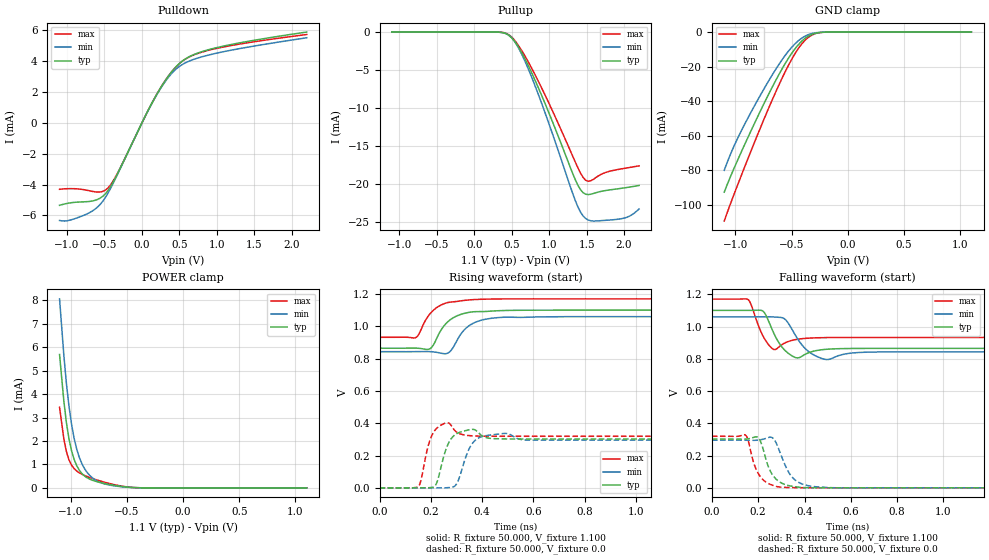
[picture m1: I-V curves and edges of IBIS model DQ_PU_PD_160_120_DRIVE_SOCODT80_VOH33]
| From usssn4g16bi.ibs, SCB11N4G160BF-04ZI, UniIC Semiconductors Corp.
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|   Model DQ_PU_PD_160_120_DRIVE_SOCODT80_VOH33
[Model] DQ_PU_PD_160_120_DRIVE_SOCODT80_VOH33
Model_type I/O
Polarity   Inverting
Vinl =  98.000mV
Vinh =  0.268V
Vmeas =  0.183V
Rref =  50.000
Vref =  0.183V
C_comp   1.020pF   1.010pF   1.030pF
[Model Spec]
Vinh   0.268V   0.262V   0.280V
Vinl   98.000mV   92.000mV   0.110V
Vmeas   0.183V   0.177V   0.195V
Vref   0.183V   0.177V   0.195V
Rref   50.000   NA   NA
[Temperature Range]   25.000   85.000   -40.000
[Voltage Range]   1.100V   1.060V   1.170V
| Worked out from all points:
|   slope of the pulldown table from 0 to 0.165 V, typ, clamps not added: 105 ohm
|   GND clamp passes 1 mA (typ) near -0.30 V on its own axis
|   POWER clamp passes 1 mA (typ) near -0.95 V on its own axis
|   rising waveform, R_fixture 50.000, V_fixture 1.100: 20-80 % time 68.7ps typ, 69.3ps min, 67.4ps max; typ from 0.864 V to 1.1 V
|   rising waveform, R_fixture 50.000, V_fixture 0.0: 20-80 % time 30.7ps typ, 37.6ps min, 25.1ps max; typ from 0 V to 0.302 V
|   falling waveform, R_fixture 50.000, V_fixture 1.100: 20-80 % time 45.3ps typ, 56.9ps min, 35.5ps max; typ from 1.1 V to 0.864 V
|   falling waveform, R_fixture 50.000, V_fixture 0.0: 20-80 % time 51.8ps typ, 61.5ps min, 48.7ps max; typ from 0.302 V to 0 V
[Pulldown]
|Voltage   I(typ)   I(min)   I(max)
-1.1V     -5.34mA    -6.324mA   -4.302mA
-964mV    -5.187mA   -6.308mA   -4.26mA
-692mV    -5.084mA   -5.795mA   -4.408mA
-556mV    -4.87mA    -5.274mA   -4.475mA
-454mV    -4.386mA   -4.558mA   -4.222mA
-318mV    -3.209mA   -3.256mA   -3.18mA
158mV     1.503mA    1.489mA    1.509mA
328mV     2.865mA    2.797mA    2.867mA
498mV     3.844mA    3.653mA    3.837mA
668mV     4.377mA    4.078mA    4.359mA
940mV     4.811mA    4.458mA    4.768mA
2.2V      5.891mA    5.519mA    5.73mA
[Pullup]
|Voltage   I(typ)   I(min)   I(max)
-1.1V     1.606nA    7.718nA    0A
296mV     -8.845uA   -10.59uA   -4.922uA
466mV     -464.7uA   -456.5uA   -387.5uA
602mV     -2.18mA    -2.299mA   -1.951mA
738mV     -4.764mA   -5.249mA   -4.236mA
976mV     -10.14mA   -11.47mA   -8.932mA
1.35V     -19.45mA   -22.19mA   -17.13mA
1.452V    -21.12mA   -24.17mA   -19.11mA
1.554V    -21.33mA   -24.82mA   -19.57mA
1.928V    -20.6mA    -24.61mA   -18.06mA
2.064V    -20.4mA    -24.25mA   -17.83mA
2.2V      -20.18mA   -23.28mA   -17.6mA
[GND_clamp]
|Voltage   I(typ)   I(min)   I(max)
-1.1V     -92.78mA   -80.14mA   -109.5mA
-1.031V   -81.73mA   -68.77mA   -97.17mA
-939mV    -68.18mA   -56.07mA   -81.64mA
-801mV    -48.85mA   -39.25mA   -59.15mA
-663mV    -30.71mA   -23.84mA   -37.89mA
-571mV    -19.76mA   -14.75mA   -24.85mA
-479mV    -10.5mA    -7.415mA   -13.5mA
-410mV    -5.313mA   -3.546mA   -6.916mA
-341mV    -2.007mA   -1.262mA   -2.59mA
-272mV    -506.9uA   -323.5uA   -609.8uA
-180mV    -45.65uA   -36.06uA   -43.55uA
1.1V      0A         0A         0A
[POWER_clamp]
|Voltage   I(typ)   I(min)   I(max)
-1.1V     5.691mA    8.066mA    3.44mA
-1.062V   3.709mA    5.665mA    2.092mA
-1.039V   2.781mA    4.457mA    1.546mA
-1.016V   2.086mA    3.48mA     1.193mA
-993mV    1.578mA    2.707mA    966.5uA
-970mV    1.21mA     2.107mA    818.5uA
-924mV    750.8uA    1.296mA    641.3uA
-878mV    507uA      821.4uA    530.2uA
-809mV    327.4uA    430uA      403.3uA
-694mV    178.4uA    161uA      233uA
-464mV    19.89uA    15.19uA    23.61uA
1.1V      0A         0A         0A
[Ramp]
| variable   typ   min   max
dV/dt_r   0.181/30.812p   0.177/37.700p   0.192/25.195p
dV/dt_f   0.141/45.332p   0.130/56.925p   0.143/35.518p
R_load = 50.000
[Rising Waveform]
R_fixture= 50.000
V_fixture= 1.100
V_fixture_min= 1.060
V_fixture_max= 1.170
|time   V(typ)   V(min)   V(max)
0s        864.4mV    842.9mV    932.1mV
141ps     864.9mV    843.2mV    930.3mV
195ps     859.6mV    843.4mV    1.074V
262ps     1.022V     831.6mV    1.146V
281ps     1.046V     855.2mV    1.151V
328ps     1.079V     973.9mV    1.16V
374ps     1.091V     1.025V     1.166V
462ps     1.096V     1.054V     1.169V
630ps     1.1V       1.059V     1.17V
3ns       1.1V       1.06V      1.17V
[Rising Waveform]
R_fixture= 50.000
V_fixture= 0.0
V_fixture_min= 0.0
V_fixture_max= 0.0
|time   V(typ)   V(min)   V(max)
0s        4.356uV    8.339uV    1.031uV
151ps     -96.84uV   43.88uV    7.108mV
190ps     269uV      3.949uV    260.9mV
217ps     12.82mV    -102.3uV   358.3mV
263ps     254.9mV    541.9uV    403.3mV
300ps     334.6mV    23.14mV    345.7mV
370ps     359.9mV    289.8mV    321.2mV
482ps     302.8mV    336.1mV    319.2mV
583ps     302.1mV    295.2mV    319.2mV
3ns       302.1mV    295.1mV    319.2mV
[Falling Waveform]
R_fixture= 50.000
V_fixture= 1.100
V_fixture_min= 1.060
V_fixture_max= 1.170
|time   V(typ)   V(min)   V(max)
0s        1.1V       1.06V      1.17V
156ps     1.1V       1.06V      1.167V
221ps     1.095V     1.06V      940.5mV
272ps     944.7mV    1.059V     856.9mV
318ps     848.8mV    1.042V     899.9mV
363ps     806.5mV    940.3mV    919.2mV
416ps     836.3mV    846.6mV    927.7mV
494ps     858.5mV    795.1mV    931.2mV
697ps     864.3mV    841.7mV    932.1mV
3ns       864.4mV    842.9mV    932.1mV
[Falling Waveform]
R_fixture= 50.000
V_fixture= 0.0
V_fixture_min= 0.0
V_fixture_max= 0.0
|time   V(typ)   V(min)   V(max)
0s        302.1mV    295.1mV    319.2mV
146ps     301.7mV    294.7mV    325.7mV
196ps     314.5mV    295mV      99.96mV
212ps     280.1mV    298.2mV    63.94mV
262ps     80.07mV    309.8mV    15.6mV
300ps     29.99mV    197.7mV    3.681mV
334ps     12.87mV    90.53mV    1.578mV
370ps     4.585mV    37.36mV    634.6uV
515ps     63.07uV    492.2uV    16.12uV
3ns       4.394uV    8.237uV    1.068uV
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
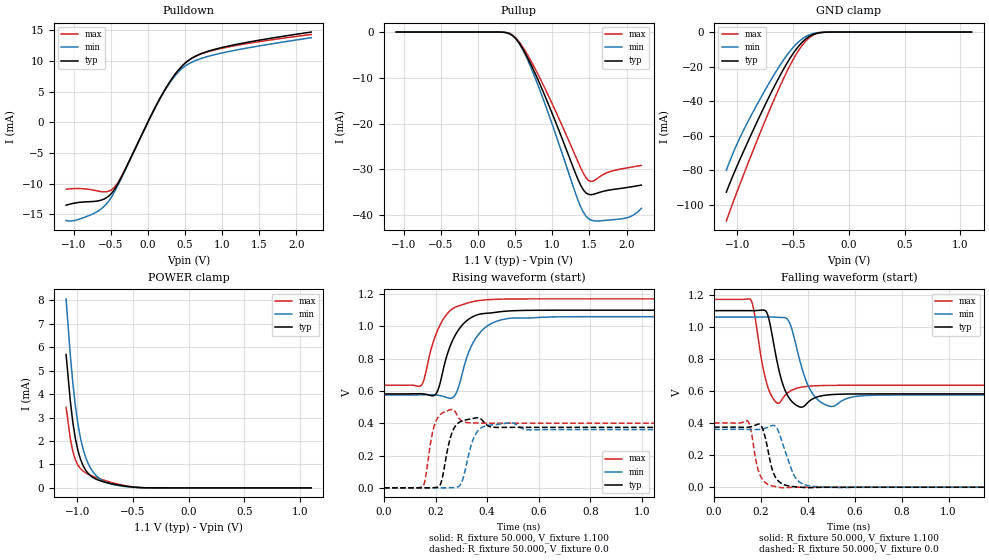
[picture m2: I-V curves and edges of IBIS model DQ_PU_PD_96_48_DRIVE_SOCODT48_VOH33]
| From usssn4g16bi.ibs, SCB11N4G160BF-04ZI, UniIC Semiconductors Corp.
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|   Model DQ_PU_PD_96_48_DRIVE_SOCODT48_VOH33
[Model] DQ_PU_PD_96_48_DRIVE_SOCODT48_VOH33
Model_type I/O
Polarity   Inverting
Vinl =  98.000mV
Vinh =  0.268V
Vmeas =  0.183V
Rref =  50.000
Vref =  0.183V
C_comp   1.020pF   1.010pF   1.030pF
[Model Spec]
Vinh   0.268V   0.262V   0.280V
Vinl   98.000mV   92.000mV   0.110V
Vmeas   0.183V   0.177V   0.195V
Vref   0.183V   0.177V   0.195V
Rref   50.000   NA   NA
[Temperature Range]   25.000   85.000   -40.000
[Voltage Range]   1.100V   1.060V   1.170V
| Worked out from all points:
|   slope of the pulldown table from 0 to 0.165 V, typ, clamps not added: 42.3 ohm
|   GND clamp passes 1 mA (typ) near -0.30 V on its own axis
|   POWER clamp passes 1 mA (typ) near -0.95 V on its own axis
|   rising waveform, R_fixture 50.000, V_fixture 1.100: 20-80 % time 74.2ps typ, 75.6ps min, 72ps max; typ from 0.582 V to 1.1 V
|   rising waveform, R_fixture 50.000, V_fixture 0.0: 20-80 % time 27.6ps typ, 34.1ps min, 22.6ps max; typ from 0 V to 0.374 V
|   falling waveform, R_fixture 50.000, V_fixture 1.100: 20-80 % time 42.9ps typ, 54.3ps min, 34.6ps max; typ from 1.1 V to 0.582 V
|   falling waveform, R_fixture 50.000, V_fixture 0.0: 20-80 % time 37.6ps typ, 53.2ps min, 33.2ps max; typ from 0.374 V to 0 V
[Pulldown]
|Voltage   I(typ)   I(min)   I(max)
-1.1V     -13.51mA   -16mA      -10.91mA
-964mV    -13.12mA   -15.94mA   -10.79mA
-692mV    -12.85mA   -14.63mA   -11.15mA
-556mV    -12.29mA   -13.29mA   -11.31mA
-454mV    -11.04mA   -11.45mA   -10.65mA
-318mV    -8.03mA    -8.142mA   -7.964mA
158mV     3.751mA    3.718mA    3.768mA
328mV     7.153mA    6.985mA    7.158mA
498mV     9.598mA    9.123mA    9.581mA
668mV     10.93mA    10.18mA    10.89mA
940mV     12.01mA    11.13mA    11.91mA
2.2V      14.71mA    13.78mA    14.31mA
[Pullup]
|Voltage   I(typ)   I(min)   I(max)
-1.1V     2.6nA      12.94nA    0A
296mV     -14.74uA   -17.65uA   -8.203uA
466mV     -773.5uA   -759.8uA   -645.2uA
602mV     -3.625mA   -3.82mA    -3.244mA
738mV     -7.914mA   -8.716mA   -7.039mA
976mV     -16.84mA   -19.04mA   -14.84mA
1.35V     -32.28mA   -36.82mA   -28.44mA
1.452V    -35.08mA   -40.12mA   -31.74mA
1.554V    -35.42mA   -41.2mA    -32.53mA
1.928V    -34.12mA   -40.78mA   -29.88mA
2.064V    -33.78mA   -40.2mA    -29.49mA
2.2V      -33.41mA   -38.49mA   -29.11mA
[GND_clamp]
|Voltage   I(typ)   I(min)   I(max)
-1.1V     -92.78mA   -80.14mA   -109.5mA
-1.031V   -81.73mA   -68.77mA   -97.17mA
-939mV    -68.18mA   -56.07mA   -81.64mA
-801mV    -48.85mA   -39.25mA   -59.15mA
-663mV    -30.71mA   -23.84mA   -37.89mA
-571mV    -19.76mA   -14.75mA   -24.85mA
-479mV    -10.5mA    -7.415mA   -13.5mA
-410mV    -5.313mA   -3.546mA   -6.916mA
-341mV    -2.007mA   -1.262mA   -2.59mA
-272mV    -506.9uA   -323.5uA   -609.8uA
-180mV    -45.65uA   -36.06uA   -43.55uA
1.1V      0A         0A         0A
[POWER_clamp]
|Voltage   I(typ)   I(min)   I(max)
-1.1V     5.691mA    8.066mA    3.44mA
-1.062V   3.709mA    5.665mA    2.092mA
-1.039V   2.781mA    4.457mA    1.546mA
-1.016V   2.086mA    3.48mA     1.193mA
-993mV    1.578mA    2.707mA    966.5uA
-970mV    1.21mA     2.107mA    818.5uA
-924mV    750.8uA    1.296mA    641.3uA
-878mV    507uA      821.4uA    530.2uA
-809mV    327.4uA    430uA      403.3uA
-694mV    178.4uA    161uA      233uA
-464mV    19.89uA    15.19uA    23.61uA
1.1V      0A         0A         0A
[Ramp]
| variable   typ   min   max
dV/dt_r   0.225/27.758p   0.216/34.246p   0.240/22.738p
dV/dt_f   0.311/42.858p   0.291/54.332p   0.321/34.656p
R_load = 50.000
[Rising Waveform]
R_fixture= 50.000
V_fixture= 1.100
V_fixture_min= 1.060
V_fixture_max= 1.170
|time   V(typ)   V(min)   V(max)
0s        581.6mV    575.3mV    635mV
144ps     582.5mV    575.8mV    633.4mV
203ps     584.3mV    575.4mV    955.7mV
267ps     915.3mV    559mV      1.11V
289ps     977.7mV    622.3mV    1.126V
330ps     1.046V     845mV      1.147V
376ps     1.077V     967.2mV    1.161V
474ps     1.094V     1.046V     1.169V
659ps     1.1V       1.058V     1.17V
3ns       1.1V       1.06V      1.17V
[Rising Waveform]
R_fixture= 50.000
V_fixture= 0.0
V_fixture_min= 0.0
V_fixture_max= 0.0
|time   V(typ)   V(min)   V(max)
0s        2.898uV    5.55uV     685nV
151ps     -60.59uV   37.16uV    9.646mV
200ps     1.978mV    -8.08uV    406.5mV
222ps     34.47mV    78.67uV    458.6mV
263ps     337.1mV    792.3uV    485.3mV
301ps     413.2mV    32.27mV    415.6mV
343ps     428.8mV    286.6mV    401.8mV
367ps     433.5mV    357.5mV    400.8mV
485ps     374.4mV    401.3mV    400.4mV
3ns       374.4mV    360.6mV    400.4mV
[Falling Waveform]
R_fixture= 50.000
V_fixture= 1.100
V_fixture_min= 1.060
V_fixture_max= 1.170
|time   V(typ)   V(min)   V(max)
0s        1.1V       1.06V      1.17V
158ps     1.1V       1.06V      1.164V
224ps     1.09V      1.06V      649.5mV
272ps     759.8mV    1.058V     522.9mV
319ps     558.3mV    1.033V     593.7mV
354ps     508mV      857.7mV    617mV
414ps     544.5mV    596.5mV    630.4mV
495ps     576.3mV    503.8mV    634.2mV
697ps     581.5mV    573.8mV    635mV
3ns       581.6mV    575.3mV    635mV
[Falling Waveform]
R_fixture= 50.000
V_fixture= 0.0
V_fixture_min= 0.0
V_fixture_max= 0.0
|time   V(typ)   V(min)   V(max)
0s        374.4mV    360.6mV    400.4mV
145ps     373.8mV    360mV      410mV
182ps     390.4mV    359.3mV    141.4mV
197ps     389.9mV    360.7mV    72.57mV
216ps     321.7mV    366.7mV    31.85mV
252ps     93.55mV    385.4mV    7.282mV
291ps     20.9mV     278.6mV    -3.476mV
348ps     3.076mV    57.54mV    -486.2uV
434ps     -1.192mV   3.908mV    -15.36uV
3ns       1.179uV    5.421uV    359.7nV
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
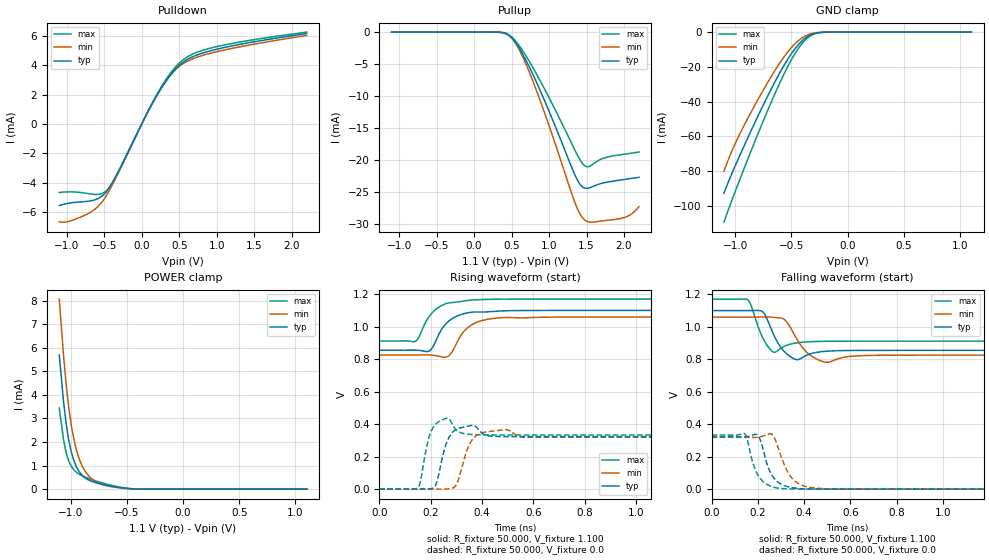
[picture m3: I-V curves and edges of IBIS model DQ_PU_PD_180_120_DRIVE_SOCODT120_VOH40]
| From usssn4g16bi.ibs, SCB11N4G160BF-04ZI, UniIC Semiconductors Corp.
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|   Model DQ_PU_PD_180_120_DRIVE_SOCODT120_VOH40
[Model] DQ_PU_PD_180_120_DRIVE_SOCODT120_VOH40
Model_type I/O
Polarity   Inverting
Vinl =  0.135V
Vinh =  0.305V
Vmeas =  0.220V
Rref =  50.000
Vref =  0.220V
C_comp   1.020pF   1.010pF   1.030pF
[Model Spec]
Vinh   0.305V   0.297V   0.319V
Vinl   0.135V   0.127V   0.149V
Vmeas   0.220V   0.212V   0.234V
Vref   0.220V   0.212V   0.234V
Rref   50.000   NA   NA
[Temperature Range]   25.000   85.000   -40.000
[Voltage Range]   1.100V   1.060V   1.170V
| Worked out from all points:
|   slope of the pulldown table from 0 to 0.165 V, typ, clamps not added: 102 ohm
|   GND clamp passes 1 mA (typ) near -0.30 V on its own axis
|   POWER clamp passes 1 mA (typ) near -0.95 V on its own axis
|   rising waveform, R_fixture 50.000, V_fixture 1.100: 20-80 % time 67.5ps typ, 68.8ps min, 68.1ps max; typ from 0.855 V to 1.1 V
|   rising waveform, R_fixture 50.000, V_fixture 0.0: 20-80 % time 28.6ps typ, 36.4ps min, 22.7ps max; typ from 0 V to 0.323 V
|   falling waveform, R_fixture 50.000, V_fixture 1.100: 20-80 % time 46.6ps typ, 59.8ps min, 37.4ps max; typ from 1.1 V to 0.855 V
|   falling waveform, R_fixture 50.000, V_fixture 0.0: 20-80 % time 51.5ps typ, 61.4ps min, 49.1ps max; typ from 0.323 V to 0 V
[Pulldown]
|Voltage   I(typ)   I(min)   I(max)
-1.1V     -5.559mA   -6.673mA   -4.673mA
-964mV    -5.394mA   -6.634mA   -4.631mA
-692mV    -5.255mA   -6.046mA   -4.769mA
-556mV    -5.011mA   -5.482mA   -4.784mA
-454mV    -4.503mA   -4.733mA   -4.479mA
-318mV    -3.293mA   -3.384mA   -3.363mA
158mV     1.547mA    1.562mA    1.602mA
328mV     2.959mA    2.962mA    3.064mA
498mV     3.986mA    3.92mA     4.137mA
668mV     4.555mA    4.415mA    4.737mA
940mV     5.019mA    4.85mA     5.2mA
2.2V      6.168mA    6.037mA    6.263mA
[Pullup]
|Voltage   I(typ)   I(min)   I(max)
-1.1V     1.8nA      9.024nA    0A
296mV     -10.32uA   -12.39uA   -5.289uA
466mV     -538.9uA   -538.1uA   -421.8uA
602mV     -2.521mA   -2.744mA   -2.134mA
738mV     -5.508mA   -6.307mA   -4.628mA
976mV     -11.74mA   -13.85mA   -9.734mA
1.35V     -22.51mA   -26.87mA   -18.62mA
1.452V    -24.32mA   -29.17mA   -20.7mA
1.52V     -24.46mA   -29.71mA   -21.11mA
1.724V    -23.63mA   -29.56mA   -19.76mA
1.962V    -23.16mA   -29.18mA   -19.2mA
2.2V      -22.76mA   -27.35mA   -18.79mA
[GND_clamp]
|Voltage   I(typ)   I(min)   I(max)
-1.1V     -92.78mA   -80.14mA   -109.5mA
-1.031V   -81.73mA   -68.77mA   -97.17mA
-939mV    -68.18mA   -56.07mA   -81.64mA
-801mV    -48.85mA   -39.25mA   -59.15mA
-663mV    -30.71mA   -23.84mA   -37.89mA
-571mV    -19.76mA   -14.75mA   -24.85mA
-479mV    -10.5mA    -7.415mA   -13.5mA
-410mV    -5.313mA   -3.546mA   -6.916mA
-341mV    -2.007mA   -1.262mA   -2.59mA
-272mV    -506.9uA   -323.5uA   -609.8uA
-180mV    -45.65uA   -36.06uA   -43.55uA
1.1V      0A         0A         0A
[POWER_clamp]
|Voltage   I(typ)   I(min)   I(max)
-1.1V     5.691mA    8.066mA    3.44mA
-1.062V   3.709mA    5.665mA    2.092mA
-1.039V   2.781mA    4.457mA    1.546mA
-1.016V   2.086mA    3.48mA     1.193mA
-993mV    1.578mA    2.707mA    966.5uA
-970mV    1.21mA     2.107mA    818.5uA
-924mV    750.8uA    1.296mA    641.3uA
-878mV    507uA      821.4uA    530.2uA
-809mV    327.4uA    430uA      403.3uA
-694mV    178.4uA    161uA      233uA
-464mV    19.89uA    15.19uA    23.61uA
1.1V      0A         0A         0A
[Ramp]
| variable   typ   min   max
dV/dt_r   0.194/28.684p   0.192/36.443p   0.200/22.890p
dV/dt_f   0.147/46.635p   0.141/59.926p   0.155/37.444p
R_load = 50.000
[Rising Waveform]
R_fixture= 50.000
V_fixture= 1.100
V_fixture_min= 1.060
V_fixture_max= 1.170
|time   V(typ)   V(min)   V(max)
0s        855mV      825.4mV    911.8mV
140ps     855.6mV    825.7mV    909.3mV
195ps     850.3mV    825.9mV    1.064V
262ps     1.021V     813.4mV    1.143V
281ps     1.046V     838.9mV    1.148V
327ps     1.079V     965.4mV    1.158V
378ps     1.091V     1.026V     1.166V
479ps     1.097V     1.056V     1.169V
726ps     1.1V       1.06V      1.17V
3ns       1.1V       1.06V      1.17V
[Rising Waveform]
R_fixture= 50.000
V_fixture= 0.0
V_fixture_min= 0.0
V_fixture_max= 0.0
|time   V(typ)   V(min)   V(max)
0s        4.316uV    8.22uV     1.011uV
150ps     -148.4uV   53.97uV    7.123mV
192ps     690.2uV    -17.05uV   309.1mV
217ps     15.99mV    -187.8uV   395.2mV
262ps     284.7mV    542.2uV    436.2mV
300ps     366.9mV    26.4mV     364.2mV
368ps     391.6mV    315.2mV    335.3mV
491ps     323.5mV    365.8mV    333.3mV
569ps     323.1mV    318.8mV    333.3mV
3ns       323.1mV    319.3mV    333.3mV
[Falling Waveform]
R_fixture= 50.000
V_fixture= 1.100
V_fixture_min= 1.060
V_fixture_max= 1.170
|time   V(typ)   V(min)   V(max)
0s        1.1V       1.06V      1.17V
157ps     1.1V       1.06V      1.166V
223ps     1.09V      1.06V      926.9mV
272ps     940.7mV    1.058V     843.2mV
316ps     845.3mV    1.044V     881.2mV
363ps     799.3mV    937.8mV    900.1mV
417ps     828.5mV    836.1mV    907.8mV
496ps     849.6mV    781.2mV    911mV
698ps     854.9mV    824.3mV    911.8mV
3ns       855mV      825.4mV    911.8mV
[Falling Waveform]
R_fixture= 50.000
V_fixture= 0.0
V_fixture_min= 0.0
V_fixture_max= 0.0
|time   V(typ)   V(min)   V(max)
0s        323.1mV    319.3mV    333.3mV
143ps     322.4mV    318.8mV    341mV
196ps     335.8mV    319.1mV    98.08mV
211ps     300.6mV    322.5mV    64.19mV
261ps     85.14mV    337.2mV    15.54mV
300ps     30.86mV    203.1mV    3.484mV
336ps     12.51mV    88.61mV    1.392mV
370ps     4.678mV    38.36mV    583.7uV
511ps     71.96uV    777.5uV    15.69uV
3ns       4.316uV    8.145uV    1.06uV
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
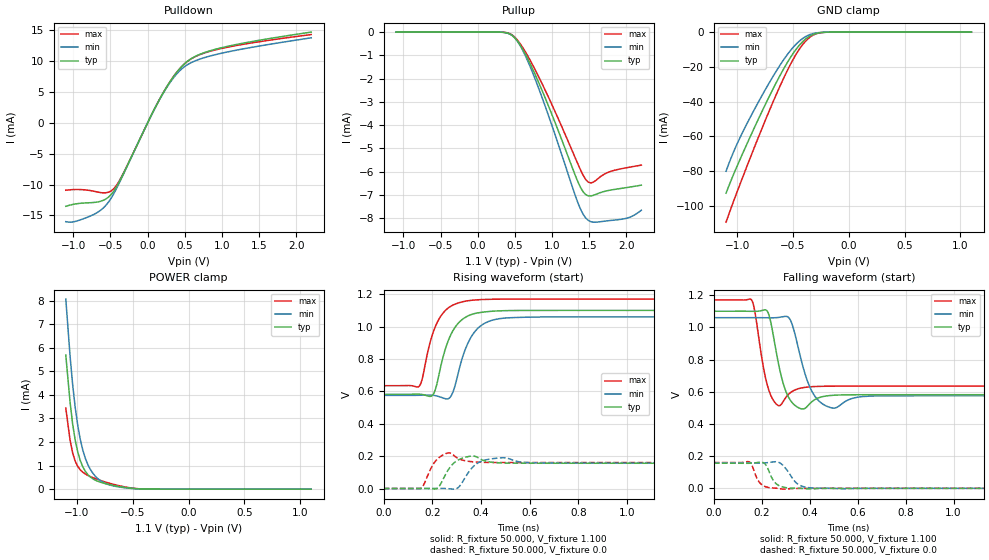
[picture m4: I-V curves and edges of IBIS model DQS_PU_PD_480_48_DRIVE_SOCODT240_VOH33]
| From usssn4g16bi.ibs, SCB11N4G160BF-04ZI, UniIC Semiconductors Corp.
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|   Model DQS_PU_PD_480_48_DRIVE_SOCODT240_VOH33
[Model] DQS_PU_PD_480_48_DRIVE_SOCODT240_VOH33
Model_type I/O
Polarity   Inverting
Vinl =  98.000mV
Vinh =  0.268V
Vmeas =  0.183V
Rref =  50.000
Vref =  0.183V
C_comp   1.020pF   1.010pF   1.030pF
[Model Spec]
Vinh   0.268V   0.262V   0.280V
Vinl   98.000mV   92.000mV   0.110V
Vmeas   0.183V   0.177V   0.195V
Vref   0.183V   0.177V   0.195V
Rref   50.000   NA   NA
[Temperature Range]   25.000   85.000   -40.000
[Voltage Range]   1.100V   1.060V   1.170V
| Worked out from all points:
|   slope of the pulldown table from 0 to 0.165 V, typ, clamps not added: 42.3 ohm
|   GND clamp passes 1 mA (typ) near -0.30 V on its own axis
|   POWER clamp passes 1 mA (typ) near -0.95 V on its own axis
|   rising waveform, R_fixture 50.000, V_fixture 1.100: 20-80 % time 69.1ps typ, 71.9ps min, 66.6ps max; typ from 0.582 V to 1.1 V
|   rising waveform, R_fixture 50.000, V_fixture 0.0: 20-80 % time 34.3ps typ, 42ps min, 28.1ps max; typ from 0 V to 0.156 V
|   falling waveform, R_fixture 50.000, V_fixture 1.100: 20-80 % time 41ps typ, 51.7ps min, 33ps max; typ from 1.1 V to 0.582 V
|   falling waveform, R_fixture 50.000, V_fixture 0.0: 20-80 % time 33.6ps typ, 47.7ps min, 30.2ps max; typ from 0.156 V to 0 V
[Pulldown]
|Voltage   I(typ)   I(min)   I(max)
-1.1V     -13.51mA   -16mA      -10.91mA
-964mV    -13.12mA   -15.94mA   -10.79mA
-692mV    -12.85mA   -14.63mA   -11.15mA
-556mV    -12.29mA   -13.29mA   -11.31mA
-454mV    -11.04mA   -11.45mA   -10.65mA
-318mV    -8.03mA    -8.142mA   -7.964mA
158mV     3.751mA    3.718mA    3.768mA
328mV     7.153mA    6.985mA    7.158mA
498mV     9.598mA    9.123mA    9.581mA
668mV     10.93mA    10.18mA    10.89mA
940mV     12.01mA    11.13mA    11.91mA
2.2V      14.71mA    13.78mA    14.31mA
[Pullup]
|Voltage   I(typ)   I(min)   I(max)
-1.1V     500pA      2.606nA    0A
296mV     -2.948uA   -3.529uA   -1.641uA
466mV     -154.8uA   -152.1uA   -129.1uA
602mV     -725.8uA   -765uA     -649.5uA
738mV     -1.585mA   -1.746mA   -1.41mA
976mV     -3.374mA   -3.816mA   -2.972mA
1.316V    -6.198mA   -7.072mA   -5.446mA
1.452V    -6.989mA   -7.995mA   -6.341mA
1.52V     -7.049mA   -8.152mA   -6.489mA
1.724V    -6.835mA   -8.124mA   -6.072mA
1.928V    -6.723mA   -8.051mA   -5.878mA
2.2V      -6.582mA   -7.66mA    -5.721mA
[GND_clamp]
|Voltage   I(typ)   I(min)   I(max)
-1.1V     -92.78mA   -80.14mA   -109.5mA
-1.031V   -81.73mA   -68.77mA   -97.17mA
-939mV    -68.18mA   -56.07mA   -81.64mA
-801mV    -48.85mA   -39.25mA   -59.15mA
-663mV    -30.71mA   -23.84mA   -37.89mA
-571mV    -19.76mA   -14.75mA   -24.85mA
-479mV    -10.5mA    -7.415mA   -13.5mA
-410mV    -5.313mA   -3.546mA   -6.916mA
-341mV    -2.007mA   -1.262mA   -2.59mA
-272mV    -506.9uA   -323.5uA   -609.8uA
-180mV    -45.65uA   -36.06uA   -43.55uA
1.1V      0A         0A         0A
[POWER_clamp]
|Voltage   I(typ)   I(min)   I(max)
-1.1V     5.691mA    8.066mA    3.44mA
-1.062V   3.709mA    5.665mA    2.092mA
-1.039V   2.781mA    4.457mA    1.546mA
-1.016V   2.086mA    3.48mA     1.193mA
-993mV    1.578mA    2.707mA    966.5uA
-970mV    1.21mA     2.107mA    818.5uA
-924mV    750.8uA    1.296mA    641.3uA
-878mV    507uA      821.4uA    530.2uA
-809mV    327.4uA    430uA      403.3uA
-694mV    178.4uA    161uA      233uA
-464mV    19.89uA    15.19uA    23.61uA
1.1V      0A         0A         0A
[Ramp]
| variable   typ   min   max
dV/dt_r   93.601m/34.336p   94.433m/42.029p   96.210m/28.199p
dV/dt_f   0.311/40.984p   0.291/51.675p   0.321/33.130p
R_load = 50.000
[Rising Waveform]
R_fixture= 50.000
V_fixture= 1.100
V_fixture_min= 1.060
V_fixture_max= 1.170
|time   V(typ)   V(min)   V(max)
0s        581.6mV    575.3mV    635mV
145ps     582.7mV    575.8mV    630.3mV
158ps     580.7mV    576.3mV    673.7mV
198ps     572mV      576.4mV    938.7mV
230ps     721.3mV    566.6mV    1.053V
271ps     932.7mV    559.4mV    1.121V
359ps     1.074V     933.9mV    1.162V
428ps     1.093V     1.03V      1.168V
539ps     1.099V     1.056V     1.17V
3ns       1.1V       1.06V      1.17V
[Rising Waveform]
R_fixture= 50.000
V_fixture= 0.0
V_fixture_min= 0.0
V_fixture_max= 0.0
|time   V(typ)   V(min)   V(max)
0s        2.898uV    5.55uV     684.5nV
153ps     275uV      4.32uV     1.551mV
221ps     2.27mV     520.8uV    182.2mV
267ps     118.5mV    -1.169mV   220.2mV
307ps     176.5mV    6.453mV    185.5mV
362ps     200.6mV    125.3mV    165.7mV
405ps     176.8mV    170.4mV    162mV
487ps     157.8mV    189.9mV    160.5mV
642ps     156mV      157.9mV    160.3mV
3ns       156mV      157.4mV    160.3mV
[Falling Waveform]
R_fixture= 50.000
V_fixture= 1.100
V_fixture_min= 1.060
V_fixture_max= 1.170
|time   V(typ)   V(min)   V(max)
0s        1.1V       1.06V      1.17V
158ps     1.1V       1.06V      1.169V
227ps     1.089V     1.06V      622.5mV
273ps     751.9mV    1.062V     513.3mV
319ps     548.2mV    1.046V     593.6mV
355ps     499.5mV    856.4mV    619.7mV
416ps     545.7mV    585mV      632mV
497ps     577.9mV    498.6mV    634.6mV
681ps     581.5mV    574.1mV    635mV
3ns       581.6mV    575.3mV    635mV
[Falling Waveform]
R_fixture= 50.000
V_fixture= 0.0
V_fixture_min= 0.0
V_fixture_max= 0.0
|time   V(typ)   V(min)   V(max)
0s        156mV      157.4mV    160.3mV
150ps     155.8mV    157.2mV    163mV
182ps     160.5mV    157mV      56.73mV
203ps     161.7mV    157.4mV    19.7mV
221ps     137.2mV    159.3mV    7.812mV
254ps     38.38mV    165.1mV    1.653mV
292ps     6.748mV    136.9mV    -5.047mV
353ps     581.5uV    24.02mV    -417.5uV
424ps     -2.128mV   1.427mV    -10.41uV
3ns       2.633uV    5.118uV    257nV
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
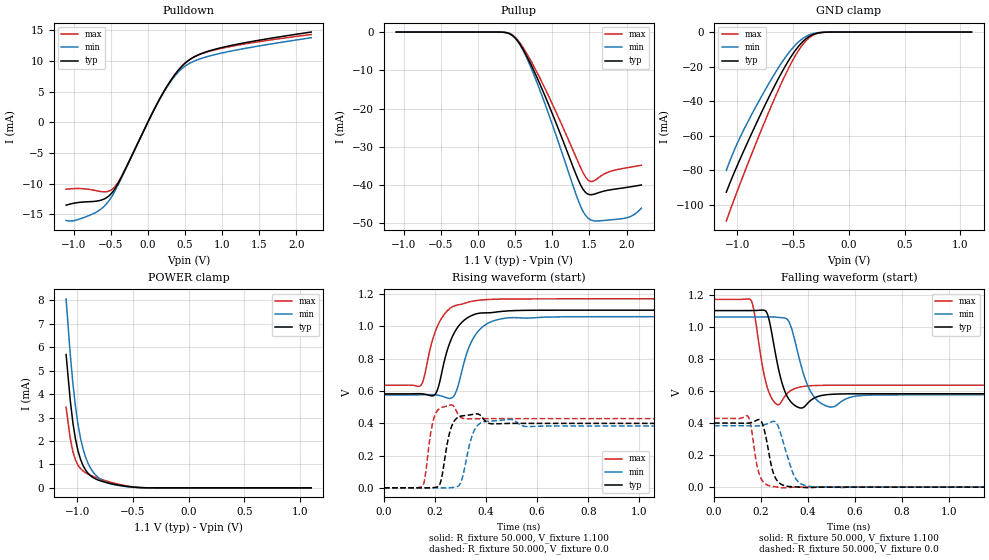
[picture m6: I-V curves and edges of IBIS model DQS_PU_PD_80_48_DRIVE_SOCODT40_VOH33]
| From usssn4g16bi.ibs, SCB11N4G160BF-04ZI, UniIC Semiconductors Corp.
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|   Model DQS_PU_PD_80_48_DRIVE_SOCODT40_VOH33
[Model] DQS_PU_PD_80_48_DRIVE_SOCODT40_VOH33
Model_type I/O
Polarity   Inverting
Vinl =  98.000mV
Vinh =  0.268V
Vmeas =  0.183V
Rref =  50.000
Vref =  0.183V
C_comp   1.020pF   1.010pF   1.030pF
[Model Spec]
Vinh   0.268V   0.262V   0.280V
Vinl   98.000mV   92.000mV   0.110V
Vmeas   0.183V   0.177V   0.195V
Vref   0.183V   0.177V   0.195V
Rref   50.000   NA   NA
[Temperature Range]   25.000   85.000   -40.000
[Voltage Range]   1.100V   1.060V   1.170V
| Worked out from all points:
|   slope of the pulldown table from 0 to 0.165 V, typ, clamps not added: 42.3 ohm
|   GND clamp passes 1 mA (typ) near -0.30 V on its own axis
|   POWER clamp passes 1 mA (typ) near -0.95 V on its own axis
|   rising waveform, R_fixture 50.000, V_fixture 1.100: 20-80 % time 67.2ps typ, 68.1ps min, 65.8ps max; typ from 0.582 V to 1.1 V
|   rising waveform, R_fixture 50.000, V_fixture 0.0: 20-80 % time 25.7ps typ, 32.5ps min, 20.8ps max; typ from 0 V to 0.399 V
|   falling waveform, R_fixture 50.000, V_fixture 1.100: 20-80 % time 41.7ps typ, 53.2ps min, 33.4ps max; typ from 1.1 V to 0.582 V
|   falling waveform, R_fixture 50.000, V_fixture 0.0: 20-80 % time 34.8ps typ, 49.8ps min, 30ps max; typ from 0.399 V to 0 V
[Pulldown]
|Voltage   I(typ)   I(min)   I(max)
-1.1V     -13.51mA   -16mA      -10.91mA
-964mV    -13.12mA   -15.94mA   -10.79mA
-692mV    -12.85mA   -14.63mA   -11.15mA
-556mV    -12.29mA   -13.29mA   -11.31mA
-454mV    -11.04mA   -11.45mA   -10.65mA
-318mV    -8.03mA    -8.142mA   -7.964mA
158mV     3.751mA    3.718mA    3.768mA
328mV     7.153mA    6.985mA    7.158mA
498mV     9.598mA    9.123mA    9.581mA
668mV     10.93mA    10.18mA    10.89mA
940mV     12.01mA    11.13mA    11.91mA
2.2V      14.71mA    13.78mA    14.31mA
[Pullup]
|Voltage   I(typ)   I(min)   I(max)
-1.1V     3.1nA      15.54nA    0A
296mV     -17.69uA   -21.17uA   -9.843uA
466mV     -927.4uA   -911uA     -773.6uA
602mV     -4.341mA   -4.574mA   -3.886mA
738mV     -9.474mA   -10.43mA   -8.429mA
976mV     -20.15mA   -22.77mA   -17.76mA
1.35V     -38.63mA   -44.04mA   -34.05mA
1.452V    -42.01mA   -48.04mA   -38mA
1.554V    -42.45mA   -49.35mA   -39mA
1.928V    -40.84mA   -48.83mA   -35.77mA
2.064V    -40.44mA   -48.15mA   -35.29mA
2.2V      -40mA      -46.05mA   -34.84mA
[GND_clamp]
|Voltage   I(typ)   I(min)   I(max)
-1.1V     -92.78mA   -80.14mA   -109.5mA
-1.031V   -81.73mA   -68.77mA   -97.17mA
-939mV    -68.18mA   -56.07mA   -81.64mA
-801mV    -48.85mA   -39.25mA   -59.15mA
-663mV    -30.71mA   -23.84mA   -37.89mA
-571mV    -19.76mA   -14.75mA   -24.85mA
-479mV    -10.5mA    -7.415mA   -13.5mA
-410mV    -5.313mA   -3.546mA   -6.916mA
-341mV    -2.007mA   -1.262mA   -2.59mA
-272mV    -506.9uA   -323.5uA   -609.8uA
-180mV    -45.65uA   -36.06uA   -43.55uA
1.1V      0A         0A         0A
[POWER_clamp]
|Voltage   I(typ)   I(min)   I(max)
-1.1V     5.691mA    8.066mA    3.44mA
-1.062V   3.709mA    5.665mA    2.092mA
-1.039V   2.781mA    4.457mA    1.546mA
-1.016V   2.086mA    3.48mA     1.193mA
-993mV    1.578mA    2.707mA    966.5uA
-970mV    1.21mA     2.107mA    818.5uA
-924mV    750.8uA    1.296mA    641.3uA
-878mV    507uA      821.4uA    530.2uA
-809mV    327.4uA    430uA      403.3uA
-694mV    178.4uA    161uA      233uA
-464mV    19.89uA    15.19uA    23.61uA
1.1V      0A         0A         0A
[Ramp]
| variable   typ   min   max
dV/dt_r   0.239/25.955p   0.230/32.576p   0.257/21.053p
dV/dt_f   0.311/41.693p   0.291/53.237p   0.321/33.560p
R_load = 50.000
[Rising Waveform]
R_fixture= 50.000
V_fixture= 1.100
V_fixture_min= 1.060
V_fixture_max= 1.170
|time   V(typ)   V(min)   V(max)
0s        581.6mV    575.3mV    635mV
144ps     582.6mV    575.8mV    633.7mV
155ps     581mV      576.2mV    670.5mV
203ps     584.4mV    575.4mV    975.2mV
264ps     921.8mV    555mV      1.117V
284ps     982.8mV    601.4mV    1.13V
337ps     1.062V     885.3mV    1.152V
376ps     1.082V     981.9mV    1.162V
510ps     1.097V     1.054V     1.17V
3ns       1.1V       1.06V      1.17V
[Rising Waveform]
R_fixture= 50.000
V_fixture= 0.0
V_fixture_min= 0.0
V_fixture_max= 0.0
|time   V(typ)   V(min)   V(max)
0s        2.898uV    5.55uV     684.5nV
152ps     -118.3uV   45.02uV    13.05mV
189ps     462.7uV    24.4uV     390.1mV
214ps     10.31mV    -30.98uV   486.1mV
225ps     55.28mV    -12.44uV   496.9mV
261ps     362mV      500uV      512.4mV
301ps     443.6mV    33.58mV    437mV
355ps     456.5mV    359.6mV    427.7mV
408ps     401.3mV    412.6mV    428.2mV
3ns       398.9mV    382.6mV    428.3mV
[Falling Waveform]
R_fixture= 50.000
V_fixture= 1.100
V_fixture_min= 1.060
V_fixture_max= 1.170
|time   V(typ)   V(min)   V(max)
0s        1.1V       1.06V      1.17V
158ps     1.1V       1.06V      1.163V
225ps     1.085V     1.06V      628.8mV
270ps     765.8mV    1.058V     513.2mV
315ps     555.4mV    1.039V     588.4mV
348ps     504.5mV    888.9mV    616.4mV
411ps     539.9mV    595.1mV    631.4mV
492ps     577.3mV    499.4mV    634.6mV
684ps     581.5mV    574.1mV    635mV
3ns       581.6mV    575.3mV    635mV
[Falling Waveform]
R_fixture= 50.000
V_fixture= 0.0
V_fixture_min= 0.0
V_fixture_max= 0.0
|time   V(typ)   V(min)   V(max)
0s        398.9mV    382.6mV    428.3mV
144ps     398.1mV    381.9mV    441.2mV
155ps     400.8mV    381.6mV    395mV
197ps     416.8mV    382.5mV    63.17mV
217ps     335.7mV    389.5mV    21.6mV
253ps     84.99mV    409.9mV    3.395mV
291ps     13.49mV    296.5mV    -4.808mV
349ps     1.061mV    49.26mV    -492.8uV
413ps     -3.056mV   3.255mV    -20.59uV
3ns       1.192uV    3.681uV    358.5nV
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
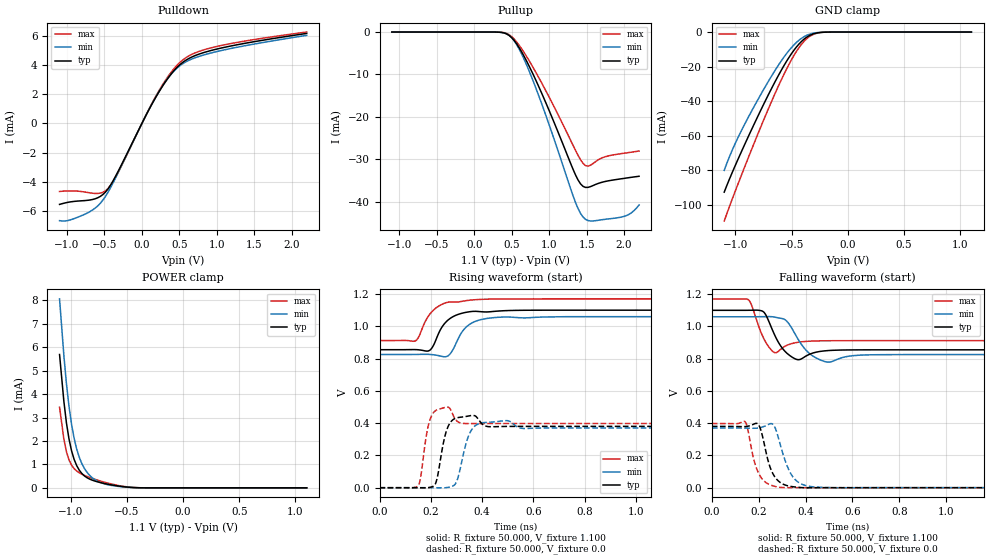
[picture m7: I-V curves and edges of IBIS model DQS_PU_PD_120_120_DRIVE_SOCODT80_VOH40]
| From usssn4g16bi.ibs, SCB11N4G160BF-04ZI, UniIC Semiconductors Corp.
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|   Model DQS_PU_PD_120_120_DRIVE_SOCODT80_VOH40
[Model] DQS_PU_PD_120_120_DRIVE_SOCODT80_VOH40
Model_type I/O
Polarity   Inverting
Vinl =  0.135V
Vinh =  0.305V
Vmeas =  0.220V
Rref =  50.000
Vref =  0.220V
C_comp   1.020pF   1.010pF   1.030pF
[Model Spec]
Vinh   0.305V   0.297V   0.319V
Vinl   0.135V   0.127V   0.149V
Vmeas   0.220V   0.212V   0.234V
Vref   0.220V   0.212V   0.234V
Rref   50.000   NA   NA
[Temperature Range]   25.000   85.000   -40.000
[Voltage Range]   1.100V   1.060V   1.170V
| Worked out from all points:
|   slope of the pulldown table from 0 to 0.165 V, typ, clamps not added: 102 ohm
|   GND clamp passes 1 mA (typ) near -0.30 V on its own axis
|   POWER clamp passes 1 mA (typ) near -0.95 V on its own axis
|   rising waveform, R_fixture 50.000, V_fixture 1.100: 20-80 % time 60.6ps typ, 60.4ps min, 63.5ps max; typ from 0.855 V to 1.1 V
|   rising waveform, R_fixture 50.000, V_fixture 0.0: 20-80 % time 25.8ps typ, 33.7ps min, 20.2ps max; typ from 0 V to 0.38 V
|   falling waveform, R_fixture 50.000, V_fixture 1.100: 20-80 % time 45.8ps typ, 60.1ps min, 36.6ps max; typ from 1.1 V to 0.855 V
|   falling waveform, R_fixture 50.000, V_fixture 0.0: 20-80 % time 46.1ps typ, 55.9ps min, 43.9ps max; typ from 0.38 V to 0 V
[Pulldown]
|Voltage   I(typ)   I(min)   I(max)
-1.1V     -5.559mA   -6.673mA   -4.673mA
-964mV    -5.394mA   -6.634mA   -4.631mA
-692mV    -5.255mA   -6.046mA   -4.769mA
-556mV    -5.011mA   -5.482mA   -4.784mA
-454mV    -4.503mA   -4.733mA   -4.479mA
-318mV    -3.293mA   -3.384mA   -3.363mA
158mV     1.547mA    1.562mA    1.602mA
328mV     2.959mA    2.962mA    3.064mA
498mV     3.986mA    3.92mA     4.137mA
668mV     4.555mA    4.415mA    4.737mA
940mV     5.019mA    4.85mA     5.2mA
2.2V      6.168mA    6.037mA    6.263mA
[Pullup]
|Voltage   I(typ)   I(min)   I(max)
-1.1V     2.7nA      13.54nA    0A
296mV     -15.48uA   -18.58uA   -7.934uA
466mV     -807.4uA   -806.2uA   -632uA
602mV     -3.772mA   -4.103mA   -3.194mA
738mV     -8.234mA   -9.422mA   -6.922mA
976mV     -17.54mA   -20.68mA   -14.55mA
1.35V     -33.63mA   -40.11mA   -27.84mA
1.452V    -36.39mA   -43.62mA   -30.97mA
1.52V     -36.62mA   -44.46mA   -31.62mA
1.724V    -35.34mA   -44.21mA   -29.55mA
1.962V    -34.61mA   -43.64mA   -28.68mA
2.2V      -34.01mA   -40.78mA   -28.06mA
[GND_clamp]
|Voltage   I(typ)   I(min)   I(max)
-1.1V     -92.78mA   -80.14mA   -109.5mA
-1.031V   -81.73mA   -68.77mA   -97.17mA
-939mV    -68.18mA   -56.07mA   -81.64mA
-801mV    -48.85mA   -39.25mA   -59.15mA
-663mV    -30.71mA   -23.84mA   -37.89mA
-571mV    -19.76mA   -14.75mA   -24.85mA
-479mV    -10.5mA    -7.415mA   -13.5mA
-410mV    -5.313mA   -3.546mA   -6.916mA
-341mV    -2.007mA   -1.262mA   -2.59mA
-272mV    -506.9uA   -323.5uA   -609.8uA
-180mV    -45.65uA   -36.06uA   -43.55uA
1.1V      0A         0A         0A
[POWER_clamp]
|Voltage   I(typ)   I(min)   I(max)
-1.1V     5.691mA    8.066mA    3.44mA
-1.062V   3.709mA    5.665mA    2.092mA
-1.039V   2.781mA    4.457mA    1.546mA
-1.016V   2.086mA    3.48mA     1.193mA
-993mV    1.578mA    2.707mA    966.5uA
-970mV    1.21mA     2.107mA    818.5uA
-924mV    750.8uA    1.296mA    641.3uA
-878mV    507uA      821.4uA    530.2uA
-809mV    327.4uA    430uA      403.3uA
-694mV    178.4uA    161uA      233uA
-464mV    19.89uA    15.19uA    23.61uA
1.1V      0A         0A         0A
[Ramp]
| variable   typ   min   max
dV/dt_r   0.228/26.023p   0.222/33.845p   0.239/20.464p
dV/dt_f   0.147/45.938p   0.141/60.086p   0.155/36.673p
R_load = 50.000
[Rising Waveform]
R_fixture= 50.000
V_fixture= 1.100
V_fixture_min= 1.060
V_fixture_max= 1.170
|time   V(typ)   V(min)   V(max)
0s        855mV      825.4mV    911.8mV
140ps     855.6mV    825.7mV    909.9mV
190ps     847.1mV    826.2mV    1.062V
205ps     867.5mV    824.6mV    1.092V
261ps     1.03V      812.5mV    1.147V
280ps     1.054V     839.2mV    1.151V
329ps     1.084V     980.4mV    1.157V
386ps     1.092V     1.037V     1.166V
492ps     1.097V     1.058V     1.17V
3ns       1.1V       1.06V      1.17V
[Rising Waveform]
R_fixture= 50.000
V_fixture= 0.0
V_fixture_min= 0.0
V_fixture_max= 0.0
|time   V(typ)   V(min)   V(max)
0s        4.315uV    8.22uV     1.011uV
152ps     -318.9uV   73.4uV     14.72mV
187ps     -55.77uV   23.29uV    362.7mV
212ps     11.68mV    -361.2uV   468.4mV
262ps     357.7mV    752.4uV    500.3mV
299ps     431.5mV    32.86mV    417.5mV
365ps     448.4mV    372mV      397.5mV
488ps     379.6mV    415.3mV    397.7mV
563ps     379.9mV    366.4mV    397.7mV
3ns       379.9mV    370mV      397.7mV
[Falling Waveform]
R_fixture= 50.000
V_fixture= 1.100
V_fixture_min= 1.060
V_fixture_max= 1.170
|time   V(typ)   V(min)   V(max)
0s        1.1V       1.06V      1.17V
158ps     1.1V       1.06V      1.162V
222ps     1.088V     1.061V     923.2mV
270ps     940.4mV    1.057V     837mV
319ps     835.7mV    1.033V     882mV
362ps     795.3mV    935.2mV    900.6mV
420ps     829.4mV    828.1mV    908.7mV
491ps     849.8mV    779.2mV    911.2mV
686ps     854.9mV    824.3mV    911.8mV
3ns       855mV      825.4mV    911.8mV
[Falling Waveform]
R_fixture= 50.000
V_fixture= 0.0
V_fixture_min= 0.0
V_fixture_max= 0.0
|time   V(typ)   V(min)   V(max)
0s        379.9mV    370mV      397.7mV
142ps     378.9mV    369.5mV    408.6mV
180ps     394.9mV    368.6mV    169.3mV
197ps     394.3mV    370mV      96.75mV
258ps     93.8mV     395.8mV    12.55mV
292ps     31.89mV    265.8mV    1.754mV
320ps     13.24mV    139.3mV    485.1uV
351ps     4.99mV     57.04mV    190.9uV
435ps     -460.9uV   4.729mV    16.24uV
3ns       4.101uV    7.948uV    976.9nV
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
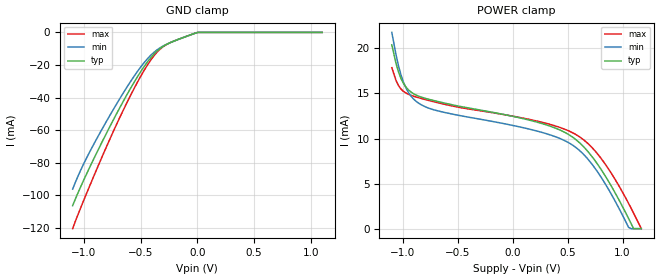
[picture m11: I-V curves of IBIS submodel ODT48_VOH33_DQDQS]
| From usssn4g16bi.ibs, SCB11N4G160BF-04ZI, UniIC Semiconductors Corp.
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|   Submodel ODT48_VOH33_DQDQS
[Submodel] ODT48_VOH33_DQDQS
Submodel_type Dynamic_clamp
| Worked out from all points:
|   GND clamp passes 1 mA (typ) near -0.04 V on its own axis
[GND_clamp]
|Voltage   I(typ)   I(min)   I(max)
-1.1V     -106.3mA   -96.14mA   -120.4mA
-1.008V   -91.48mA   -81.44mA   -104mA
-916mV    -77.93mA   -68.91mA   -88.62mA
-755mV    -55.56mA   -48.95mA   -62.89mA
-617mV    -37.72mA   -33.14mA   -42.52mA
-525mV    -26.86mA   -23.63mA   -30.11mA
-456mV    -19.65mA   -17.45mA   -21.75mA
-387mV    -13.67mA   -12.49mA   -14.72mA
-318mV    -9.359mA   -8.972mA   -9.653mA
-226mV    -5.885mA   -5.884mA   -5.886mA
4mV       0A         0A         0A
1.1V      0A         0A         0A
[POWER_clamp]
|Voltage   I(typ)   I(min)   I(max)
-1.1V     20.4mA     21.77mA    17.86mA
-1.039V   17.38mA    18.05mA    15.87mA
-993mV    16.09mA    16.22mA    15.22mA
-924mV    15.14mA    14.68mA    14.79mA
-855mV    14.7mA     13.91mA    14.52mA
-648mV    14.01mA    12.97mA    13.87mA
249mV     11.72mA    10.74mA    11.85mA
594mV     9.684mA    8.82mA     10.3mA
801mV     6.63mA     5.771mA    7.844mA
1.054V    1.14mA     150.2uA    2.816mA
1.1V      0A         0A         1.731mA
1.17V     0A         0A         0A
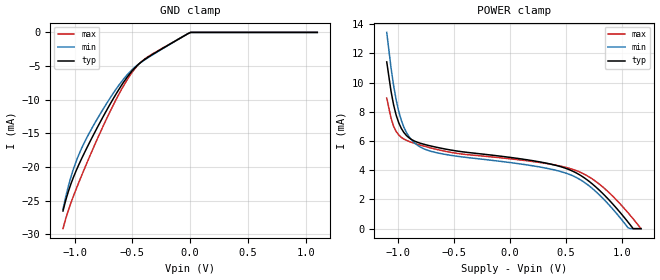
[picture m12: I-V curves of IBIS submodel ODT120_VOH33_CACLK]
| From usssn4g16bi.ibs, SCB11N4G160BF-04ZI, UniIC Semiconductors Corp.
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|   Submodel ODT120_VOH33_CACLK
[Submodel] ODT120_VOH33_CACLK
Submodel_type Dynamic_clamp
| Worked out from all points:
|   GND clamp passes 1 mA (typ) near -0.10 V on its own axis
[GND_clamp]
|Voltage   I(typ)   I(min)   I(max)
-1.1V     -26.53mA   -26.29mA   -29.16mA
-1.054V   -23.66mA   -22.88mA   -26.46mA
-1.008V   -21.46mA   -20.22mA   -24.25mA
-939mV    -18.77mA   -17.22mA   -21.28mA
-870mV    -16.35mA   -14.87mA   -18.47mA
-732mV    -11.87mA   -10.82mA   -13.17mA
-594mV    -7.871mA   -7.328mA   -8.485mA
-502mV    -5.715mA   -5.536mA   -5.931mA
-410mV    -4.23mA    -4.273mA   -4.183mA
-318mV    -3.197mA   -3.259mA   -3.124mA
4mV       0A         0A         0A
1.1V      0A         0A         0A
[POWER_clamp]
|Voltage   I(typ)   I(min)   I(max)
-1.1V     11.42mA    13.44mA    8.941mA
-1.039V   8.483mA    9.812mA    7.018mA
-993mV    7.251mA    8.036mA    6.413mA
-924mV    6.377mA    6.579mA    6.048mA
-832mV    5.933mA    5.748mA    5.794mA
-579mV    5.454mA    5.088mA    5.299mA
295mV     4.529mA    4.183mA    4.498mA
594mV     3.807mA    3.496mA    3.967mA
801mV     2.61mA     2.292mA    3.029mA
1.054V    448.8uA    59.78uA    1.088mA
1.1V      0A         0A         668.5uA
1.17V     0A         0A         0A
